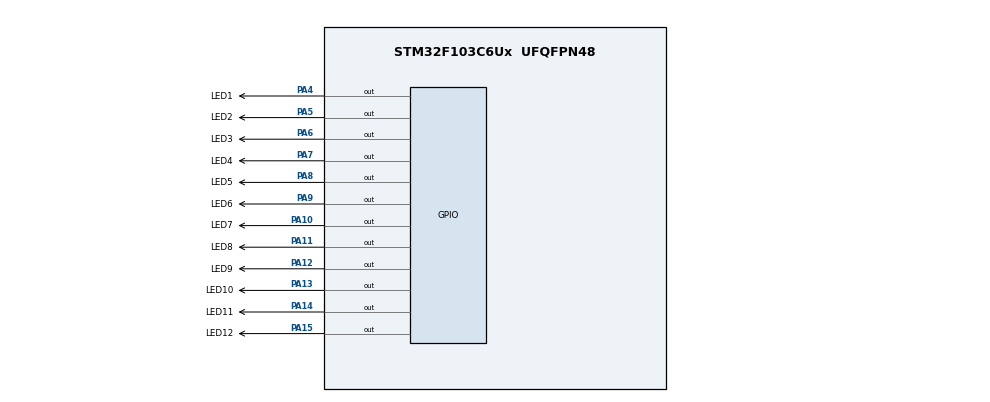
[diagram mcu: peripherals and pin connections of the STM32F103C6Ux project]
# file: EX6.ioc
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Mcu.Family=STM32F1
Mcu.Name=STM32F103C6Ux
Mcu.Package=UFQFPN48
NVIC.PriorityGroup=NVIC_PRIORITYGROUP_4
PA10.GPIO_Label=LED7
PA10.Signal=GPIO_Output
PA11.GPIO_Label=LED8
PA11.Signal=GPIO_Output
PA12.GPIO_Label=LED9
PA12.Signal=GPIO_Output
PA13.GPIO_Label=LED10
PA13.Signal=GPIO_Output
PA14.GPIO_Label=LED11
PA14.Signal=GPIO_Output
PA15.GPIO_Label=LED12
PA15.Signal=GPIO_Output
PA4.GPIO_Label=LED1
PA4.Signal=GPIO_Output
PA5.GPIO_Label=LED2
PA5.Signal=GPIO_Output
PA6.GPIO_Label=LED3
PA6.Signal=GPIO_Output
PA7.GPIO_Label=LED4
PA7.Signal=GPIO_Output
PA8.GPIO_Label=LED5
PA8.Signal=GPIO_Output
PA9.GPIO_Label=LED6
PA9.Signal=GPIO_Output
ProjectManager.HeapSize=0x200
ProjectManager.StackSize=0x400
ProjectManager.TargetToolchain=STM32CubeIDE
RCC.APB1Freq_Value=8000000
RCC.APB2Freq_Value=8000000
VP_SYS_VS_ND.Mode=No_Debug
board=custom

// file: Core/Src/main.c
/* USER CODE BEGIN Header */
/**
  ******************************************************************************
  * @file           : main.c
  * @brief          : Main program body
  ******************************************************************************
  * @attention
  *
  * <h2><center>&copy; Copyright (c) 2023 STMicroelectronics.
  * All rights reserved.</center></h2>
  *
  * This software component is licensed by ST under BSD 3-Clause license,
  * the "License"; You may not use this file except in compliance with the
  * License. You may obtain a copy of the License at:
  *                        opensource.org/licenses/BSD-3-Clause
  *
  ******************************************************************************
  */
/* USER CODE END Header */
#include "main.h"

#define RED 5
#define GREEN 3
#define YELLOW 2

void SystemClock_Config(void);
static void MX_GPIO_Init(void);

int main(void)
{

  /* MCU Configuration--------------------------------------------------------*/

  /* Reset of all peripherals, Initializes the Flash interface and the Systick. */
  HAL_Init();

  /* Configure the system clock */
  SystemClock_Config();

  /* Initialize all configured peripherals */
  MX_GPIO_Init();

  /* Infinite loop */
  /* USER CODE BEGIN WHILE */

  void display(int led, GPIO_PinState a, GPIO_PinState b,
  		GPIO_PinState c, GPIO_PinState d, GPIO_PinState e, GPIO_PinState f,
  		GPIO_PinState g) {
	  if(led==1){
		  HAL_GPIO_WritePin(GPIOB, GPIO_PIN_0, a);
		  HAL_GPIO_WritePin(GPIOB, GPIO_PIN_1, b);
		  HAL_GPIO_WritePin(GPIOB, GPIO_PIN_2, c);
		  HAL_GPIO_WritePin(GPIOB, GPIO_PIN_3, d);
		  HAL_GPIO_WritePin(GPIOB, GPIO_PIN_4, e);
		  HAL_GPIO_WritePin(GPIOB, GPIO_PIN_5, f);
		  HAL_GPIO_WritePin(GPIOB, GPIO_PIN_6, g);
	  }
	  if (led == 2){
		  HAL_GPIO_WritePin(GPIOB, GPIO_PIN_7, a);
		  HAL_GPIO_WritePin(GPIOB, GPIO_PIN_8, b);
		  HAL_GPIO_WritePin(GPIOB, GPIO_PIN_9, c);
		  HAL_GPIO_WritePin(GPIOB, GPIO_PIN_10, d);
		  HAL_GPIO_WritePin(GPIOB, GPIO_PIN_11, e);
		  HAL_GPIO_WritePin(GPIOB, GPIO_PIN_12, f);
		  HAL_GPIO_WritePin(GPIOB, GPIO_PIN_13, g);
	  }

  }

  void display7SEG(int led,int state){
		switch (state) {
		case 0:
		  	display(led,0, 0, 0, 0, 0, 0, 1);
		  		  break;
		  	case 1:
		  		  display(led, 1, 0, 0, 1, 1, 1, 1);
		  		  break;
		  	  case 2:
		  		  display(led, 0, 0, 1, 0, 0, 1, 0);
		  		  break;
		  	  case 3:
		  		  display(led, 0, 0, 0, 0, 1, 1, 0);
		  		  break;
		  	  case 4:
		  		  display(led, 1, 0, 0, 1, 1, 0, 0);
		  		  break;
		  	  case 5:
		  		  display(led, 0, 1, 0, 0, 1, 0, 0);
		  		  break;
		  	  case 6:
		  		  display(led, 0, 1, 0, 0, 0, 0, 0);
		  		  break;
		  	  case 7:
		  		  display(led, 0, 0, 0, 1, 1, 1, 1);
		  		  break;
		  	  case 8:
		  		  display(led, 0, 0, 0, 0, 0, 0, 0);
		  		  break;
		  	  case 9:
		  		  display(led, 0, 0, 0, 0, 1, 0, 0);
		  		  break;
		  	  default:
		  		  display(led, 1, 1, 1, 1, 1, 1, 1);

	  }

    }

    int counter=0;
    int led_state=0;
    int counterA = RED;
    int counterB = GREEN;
    int counterC = YELLOW;
	while (1)
    {
    	if(led_state==0){
    		if(counter < GREEN){
    			//trang thai : led_red_1,led_green_2: ON
    			//			   led_yellow_1,led_green_1,led_red_2,led_yellow_2:OFF
    			HAL_GPIO_WritePin(LED_RED1_GPIO_Port, LED_RED1_Pin,1);
    			HAL_GPIO_WritePin(LED_YELLOW1_GPIO_Port, LED_YELLOW1_Pin,0);
    			HAL_GPIO_WritePin(LED_GREEN1_GPIO_Port, LED_GREEN1_Pin,0);
    			HAL_GPIO_WritePin(LED_RED2_GPIO_Port, LED_RED2_Pin,0);
    			HAL_GPIO_WritePin(LED_YELLOW2_GPIO_Port, LED_YELLOW2_Pin,0);
    			HAL_GPIO_WritePin(LED_GREEN2_GPIO_Port, LED_GREEN2_Pin,1);
    			display7SEG(1, counterA);
    			display7SEG(2, counterB);
    			counterA--;
    			counterB--;

    		}
    		if(counter >= GREEN && counter < RED){
    		    //trang thai : led_red_1,led_yellow_2: ON
    		    //			   led_yellow_1,led_green_1,led_red_2,led_green_2:OFF
    		    HAL_GPIO_WritePin(LED_RED1_GPIO_Port, LED_RED1_Pin,1);
    		    HAL_GPIO_WritePin(LED_YELLOW1_GPIO_Port, LED_YELLOW1_Pin,0);
    		    HAL_GPIO_WritePin(LED_GREEN1_GPIO_Port, LED_GREEN1_Pin,0);
    		    HAL_GPIO_WritePin(LED_RED2_GPIO_Port, LED_RED2_Pin,0);
    		    HAL_GPIO_WritePin(LED_YELLOW2_GPIO_Port, LED_YELLOW2_Pin,1);
    		    HAL_GPIO_WritePin(LED_GREEN2_GPIO_Port, LED_GREEN2_Pin,0);
    			display7SEG(1, counterA);
    			display7SEG(2, counterC);
    			counterA--;
    			counterC--;
    		    if(counter >= RED - 1){
    		    	//set lai state
    		    	led_state=1;
       		        counterA = RED;
        		    counterB = GREEN;
        		    counterC = YELLOW;
    		    }
    		}
    	}

    	if(led_state == 1){
    		if(counter >= RED && counter < RED + GREEN){
    			//trang thai : led_red_2,led_green_1: ON
    			//			   led_yellow_1,led_red_1,led_green_2,led_yellow_2:OFF
    			HAL_GPIO_WritePin(LED_RED1_GPIO_Port, LED_RED1_Pin,0);
    			HAL_GPIO_WritePin(LED_YELLOW1_GPIO_Port, LED_YELLOW1_Pin,0);
    			HAL_GPIO_WritePin(LED_GREEN1_GPIO_Port, LED_GREEN1_Pin,1);
    			HAL_GPIO_WritePin(LED_RED2_GPIO_Port, LED_RED2_Pin,1);
    			HAL_GPIO_WritePin(LED_YELLOW2_GPIO_Port, LED_YELLOW2_Pin,0);
    			HAL_GPIO_WritePin(LED_GREEN2_GPIO_Port, LED_GREEN2_Pin,0);
    			display7SEG(2, counterA);
    			display7SEG(1, counterB);
    			counterA--;
    			counterB--;

    		}
    		if(counter >= RED + GREEN && counter < RED + GREEN + YELLOW){
    		    //trang thai : led_red_2,led_yellow_1: ON
    		    //			   led_red_1,led_green_1,led_green_2,led_green_2:OFF
    		    HAL_GPIO_WritePin(LED_RED1_GPIO_Port, LED_RED1_Pin,1);
    		    HAL_GPIO_WritePin(LED_YELLOW1_GPIO_Port, LED_YELLOW1_Pin,0);
    		    HAL_GPIO_WritePin(LED_GREEN1_GPIO_Port, LED_GREEN1_Pin,0);
    		    HAL_GPIO_WritePin(LED_RED2_GPIO_Port, LED_RED2_Pin,0);
    		    HAL_GPIO_WritePin(LED_YELLOW2_GPIO_Port, LED_YELLOW2_Pin,1);
    		    HAL_GPIO_WritePin(LED_GREEN2_GPIO_Port, LED_GREEN2_Pin,0);
    			display7SEG(2, counterA);
    			display7SEG(1, counterC);
    			counterA--;
    			counterC--;
    		}
    	}

    	counter++;
    	if(counter >= RED + GREEN + YELLOW){
    		//set lai state
    		counter = 0;
    		led_state = 0;
	        counterA = RED;
	        counterB = GREEN;
	        counterC = YELLOW;
    	}

    	HAL_Delay(1000);

    /* USER CODE END WHILE */

  }
}

void SystemClock_Config(void)
{
  RCC_OscInitTypeDef RCC_OscInitStruct = {0};
  RCC_ClkInitTypeDef RCC_ClkInitStruct = {0};

  /** Initializes the RCC Oscillators according to the specified parameters
  * in the RCC_OscInitTypeDef structure.
  */
  RCC_OscInitStruct.OscillatorType = RCC_OSCILLATORTYPE_HSI;
  RCC_OscInitStruct.HSIState = RCC_HSI_ON;
  RCC_OscInitStruct.HSICalibrationValue = RCC_HSICALIBRATION_DEFAULT;
  RCC_OscInitStruct.PLL.PLLState = RCC_PLL_NONE;
  if (HAL_RCC_OscConfig(&RCC_OscInitStruct) != HAL_OK)
  {
    Error_Handler();
  }
  /** Initializes the CPU, AHB and APB buses clocks
  */
  RCC_ClkInitStruct.ClockType = RCC_CLOCKTYPE_HCLK|RCC_CLOCKTYPE_SYSCLK
                              |RCC_CLOCKTYPE_PCLK1|RCC_CLOCKTYPE_PCLK2;
  RCC_ClkInitStruct.SYSCLKSource = RCC_SYSCLKSOURCE_HSI;
  RCC_ClkInitStruct.AHBCLKDivider = RCC_SYSCLK_DIV1;
  RCC_ClkInitStruct.APB1CLKDivider = RCC_HCLK_DIV1;
  RCC_ClkInitStruct.APB2CLKDivider = RCC_HCLK_DIV1;

  if (HAL_RCC_ClockConfig(&RCC_ClkInitStruct, FLASH_LATENCY_0) != HAL_OK)
  {
    Error_Handler();
  }
}

static void MX_GPIO_Init(void)
{
  GPIO_InitTypeDef GPIO_InitStruct = {0};

  /* GPIO Ports Clock Enable */
  __HAL_RCC_GPIOA_CLK_ENABLE();
  __HAL_RCC_GPIOB_CLK_ENABLE();

  /*Configure GPIO pin Output Level */
  HAL_GPIO_WritePin(GPIOA, LED_RED1_Pin|LED_YELLOW1_Pin|LED_GREEN1_Pin|LED_RED2_Pin
                          |LED_YELLOW2_Pin|LED_GREEN2_Pin, GPIO_PIN_RESET);

  /*Configure GPIO pin Output Level */
  HAL_GPIO_WritePin(GPIOB, GPIO_PIN_0|GPIO_PIN_1|GPIO_PIN_2|GPIO_PIN_10
                          |GPIO_PIN_11|GPIO_PIN_12|GPIO_PIN_13|GPIO_PIN_3
                          |GPIO_PIN_4|GPIO_PIN_5|GPIO_PIN_6|GPIO_PIN_7
                          |GPIO_PIN_8|GPIO_PIN_9, GPIO_PIN_RESET);

  /*Configure GPIO pins : LED_RED1_Pin LED_YELLOW1_Pin LED_GREEN1_Pin LED_RED2_Pin
                           LED_YELLOW2_Pin LED_GREEN2_Pin */
  GPIO_InitStruct.Pin = LED_RED1_Pin|LED_YELLOW1_Pin|LED_GREEN1_Pin|LED_RED2_Pin
                          |LED_YELLOW2_Pin|LED_GREEN2_Pin;
  GPIO_InitStruct.Mode = GPIO_MODE_OUTPUT_PP;
  GPIO_InitStruct.Pull = GPIO_NOPULL;
  GPIO_InitStruct.Speed = GPIO_SPEED_FREQ_LOW;
  HAL_GPIO_Init(GPIOA, &GPIO_InitStruct);

  /*Configure GPIO pins : PB0 PB1 PB2 PB10
                           PB11 PB12 PB13 PB3
                           PB4 PB5 PB6 PB7
                           PB8 PB9 */
  GPIO_InitStruct.Pin = GPIO_PIN_0|GPIO_PIN_1|GPIO_PIN_2|GPIO_PIN_10
                          |GPIO_PIN_11|GPIO_PIN_12|GPIO_PIN_13|GPIO_PIN_3
                          |GPIO_PIN_4|GPIO_PIN_5|GPIO_PIN_6|GPIO_PIN_7
                          |GPIO_PIN_8|GPIO_PIN_9;
  GPIO_InitStruct.Mode = GPIO_MODE_OUTPUT_PP;
  GPIO_InitStruct.Pull = GPIO_NOPULL;
  GPIO_InitStruct.Speed = GPIO_SPEED_FREQ_LOW;
  HAL_GPIO_Init(GPIOB, &GPIO_InitStruct);

}

void Error_Handler(void)
{
  __disable_irq();
  while (1)
  {
  }
}

/************************ (C) COPYRIGHT STMicroelectronics *****END OF FILE****/
